VERSION 5.7 ;
  NOWIREEXTENSIONATPIN ON ;
  DIVIDERCHAR "/" ;
  BUSBITCHARS "[]" ;
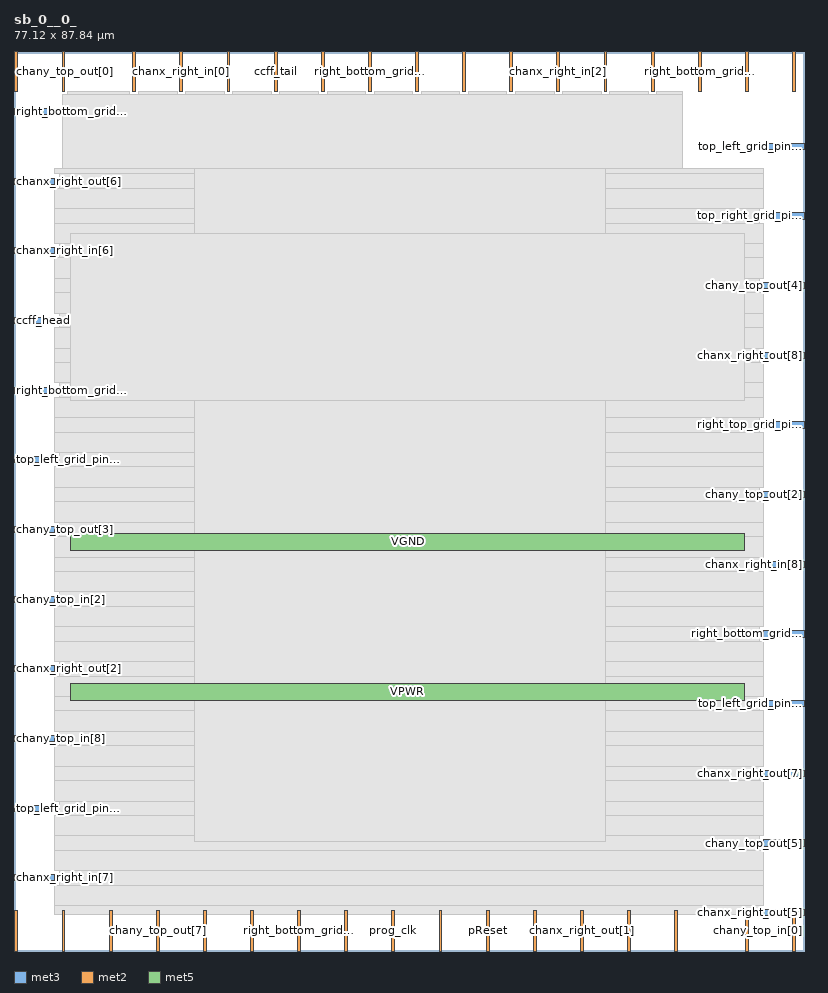
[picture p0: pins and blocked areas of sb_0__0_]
MACRO sb_0__0_
  CLASS BLOCK ;
  FOREIGN sb_0__0_ ;
  ORIGIN 0.000 0.000 ;
  SIZE 77.120 BY 87.840 ;
  PIN ccff_head
    DIRECTION INPUT ;
    PORT
      LAYER met3 ;
        RECT 0.000 61.240 4.000 61.840 ;
    END
  END ccff_head
  PIN ccff_tail
    DIRECTION OUTPUT TRISTATE ;
    PORT
      LAYER met2 ;
        RECT 25.390 83.840 25.670 87.840 ;
    END
  END ccff_tail
  PIN chanx_right_in[0]
    DIRECTION INPUT ;
    PORT
      LAYER met2 ;
        RECT 16.190 83.840 16.470 87.840 ;
    END
  END chanx_right_in[0]
  PIN chanx_right_in[1]
    DIRECTION INPUT ;
    PORT
      LAYER met2 ;
        RECT 0.090 83.840 0.370 87.840 ;
    END
  END chanx_right_in[1]
  PIN chanx_right_in[2]
    DIRECTION INPUT ;
    PORT
      LAYER met2 ;
        RECT 52.990 83.840 53.270 87.840 ;
    END
  END chanx_right_in[2]
  PIN chanx_right_in[3]
    DIRECTION INPUT ;
    PORT
      LAYER met2 ;
        RECT 41.490 0.000 41.770 4.000 ;
    END
  END chanx_right_in[3]
  PIN chanx_right_in[4]
    DIRECTION INPUT ;
    PORT
      LAYER met2 ;
        RECT 50.690 0.000 50.970 4.000 ;
    END
  END chanx_right_in[4]
  PIN chanx_right_in[5]
    DIRECTION INPUT ;
    PORT
      LAYER met2 ;
        RECT 43.790 83.840 44.070 87.840 ;
    END
  END chanx_right_in[5]
  PIN chanx_right_in[6]
    DIRECTION INPUT ;
    PORT
      LAYER met3 ;
        RECT 0.000 68.040 4.000 68.640 ;
    END
  END chanx_right_in[6]
  PIN chanx_right_in[7]
    DIRECTION INPUT ;
    PORT
      LAYER met3 ;
        RECT 0.000 6.840 4.000 7.440 ;
    END
  END chanx_right_in[7]
  PIN chanx_right_in[8]
    DIRECTION INPUT ;
    PORT
      LAYER met3 ;
        RECT 73.120 37.440 77.120 38.040 ;
    END
  END chanx_right_in[8]
  PIN chanx_right_out[0]
    DIRECTION OUTPUT TRISTATE ;
    PORT
      LAYER met2 ;
        RECT 11.590 83.840 11.870 87.840 ;
    END
  END chanx_right_out[0]
  PIN chanx_right_out[1]
    DIRECTION OUTPUT TRISTATE ;
    PORT
      LAYER met2 ;
        RECT 55.290 0.000 55.570 4.000 ;
    END
  END chanx_right_out[1]
  PIN chanx_right_out[2]
    DIRECTION OUTPUT TRISTATE ;
    PORT
      LAYER met3 ;
        RECT 0.000 27.240 4.000 27.840 ;
    END
  END chanx_right_out[2]
  PIN chanx_right_out[3]
    DIRECTION OUTPUT TRISTATE ;
    PORT
      LAYER met2 ;
        RECT 57.590 83.840 57.870 87.840 ;
    END
  END chanx_right_out[3]
  PIN chanx_right_out[4]
    DIRECTION OUTPUT TRISTATE ;
    PORT
      LAYER met2 ;
        RECT 9.290 0.000 9.570 4.000 ;
    END
  END chanx_right_out[4]
  PIN chanx_right_out[5]
    DIRECTION OUTPUT TRISTATE ;
    PORT
      LAYER met3 ;
        RECT 73.120 3.440 77.120 4.040 ;
    END
  END chanx_right_out[5]
  PIN chanx_right_out[6]
    DIRECTION OUTPUT TRISTATE ;
    PORT
      LAYER met3 ;
        RECT 0.000 74.840 4.000 75.440 ;
    END
  END chanx_right_out[6]
  PIN chanx_right_out[7]
    DIRECTION OUTPUT TRISTATE ;
    PORT
      LAYER met3 ;
        RECT 73.120 17.040 77.120 17.640 ;
    END
  END chanx_right_out[7]
  PIN chanx_right_out[8]
    DIRECTION OUTPUT TRISTATE ;
    PORT
      LAYER met3 ;
        RECT 73.120 57.840 77.120 58.440 ;
    END
  END chanx_right_out[8]
  PIN chany_top_in[0]
    DIRECTION INPUT ;
    PORT
      LAYER met2 ;
        RECT 75.990 0.000 76.270 4.000 ;
    END
  END chany_top_in[0]
  PIN chany_top_in[1]
    DIRECTION INPUT ;
    PORT
      LAYER met2 ;
        RECT 29.990 83.840 30.270 87.840 ;
    END
  END chany_top_in[1]
  PIN chany_top_in[2]
    DIRECTION INPUT ;
    PORT
      LAYER met3 ;
        RECT 0.000 34.040 4.000 34.640 ;
    END
  END chany_top_in[2]
  PIN chany_top_in[3]
    DIRECTION INPUT ;
    PORT
      LAYER met2 ;
        RECT 71.390 0.000 71.670 4.000 ;
    END
  END chany_top_in[3]
  PIN chany_top_in[4]
    DIRECTION INPUT ;
    PORT
      LAYER met2 ;
        RECT 48.390 83.840 48.670 87.840 ;
    END
  END chany_top_in[4]
  PIN chany_top_in[5]
    DIRECTION INPUT ;
    PORT
      LAYER met2 ;
        RECT 23.090 0.000 23.370 4.000 ;
    END
  END chany_top_in[5]
  PIN chany_top_in[6]
    DIRECTION INPUT ;
    PORT
      LAYER met2 ;
        RECT 39.190 83.840 39.470 87.840 ;
    END
  END chany_top_in[6]
  PIN chany_top_in[7]
    DIRECTION INPUT ;
    PORT
      LAYER met2 ;
        RECT 64.490 0.000 64.770 4.000 ;
    END
  END chany_top_in[7]
  PIN chany_top_in[8]
    DIRECTION INPUT ;
    PORT
      LAYER met3 ;
        RECT 0.000 20.440 4.000 21.040 ;
    END
  END chany_top_in[8]
  PIN chany_top_out[0]
    DIRECTION OUTPUT TRISTATE ;
    PORT
      LAYER met2 ;
        RECT 4.690 83.840 4.970 87.840 ;
    END
  END chany_top_out[0]
  PIN chany_top_out[1]
    DIRECTION OUTPUT TRISTATE ;
    PORT
      LAYER met2 ;
        RECT 32.290 0.000 32.570 4.000 ;
    END
  END chany_top_out[1]
  PIN chany_top_out[2]
    DIRECTION OUTPUT TRISTATE ;
    PORT
      LAYER met3 ;
        RECT 73.120 44.240 77.120 44.840 ;
    END
  END chany_top_out[2]
  PIN chany_top_out[3]
    DIRECTION OUTPUT TRISTATE ;
    PORT
      LAYER met3 ;
        RECT 0.000 40.840 4.000 41.440 ;
    END
  END chany_top_out[3]
  PIN chany_top_out[4]
    DIRECTION OUTPUT TRISTATE ;
    PORT
      LAYER met3 ;
        RECT 73.120 64.640 77.120 65.240 ;
    END
  END chany_top_out[4]
  PIN chany_top_out[5]
    DIRECTION OUTPUT TRISTATE ;
    PORT
      LAYER met3 ;
        RECT 73.120 10.240 77.120 10.840 ;
    END
  END chany_top_out[5]
  PIN chany_top_out[6]
    DIRECTION OUTPUT TRISTATE ;
    PORT
      LAYER met2 ;
        RECT 18.490 0.000 18.770 4.000 ;
    END
  END chany_top_out[6]
  PIN chany_top_out[7]
    DIRECTION OUTPUT TRISTATE ;
    PORT
      LAYER met2 ;
        RECT 13.890 0.000 14.170 4.000 ;
    END
  END chany_top_out[7]
  PIN chany_top_out[8]
    DIRECTION OUTPUT TRISTATE ;
    PORT
      LAYER met2 ;
        RECT 59.890 0.000 60.170 4.000 ;
    END
  END chany_top_out[8]
  PIN pReset
    DIRECTION INPUT ;
    PORT
      LAYER met2 ;
        RECT 46.090 0.000 46.370 4.000 ;
    END
  END pReset
  PIN prog_clk
    DIRECTION INPUT ;
    PORT
      LAYER met2 ;
        RECT 36.890 0.000 37.170 4.000 ;
    END
  END prog_clk
  PIN right_bottom_grid_pin_11_
    DIRECTION INPUT ;
    PORT
      LAYER met2 ;
        RECT 27.690 0.000 27.970 4.000 ;
    END
  END right_bottom_grid_pin_11_
  PIN right_bottom_grid_pin_13_
    DIRECTION INPUT ;
    PORT
      LAYER met3 ;
        RECT 0.000 81.640 4.000 82.240 ;
    END
  END right_bottom_grid_pin_13_
  PIN right_bottom_grid_pin_15_
    DIRECTION INPUT ;
    PORT
      LAYER met2 ;
        RECT 4.690 0.000 4.970 4.000 ;
    END
  END right_bottom_grid_pin_15_
  PIN right_bottom_grid_pin_1_
    DIRECTION INPUT ;
    PORT
      LAYER met2 ;
        RECT 62.190 83.840 62.470 87.840 ;
    END
  END right_bottom_grid_pin_1_
  PIN right_bottom_grid_pin_3_
    DIRECTION INPUT ;
    PORT
      LAYER met3 ;
        RECT 73.120 30.640 77.120 31.240 ;
    END
  END right_bottom_grid_pin_3_
  PIN right_bottom_grid_pin_5_
    DIRECTION INPUT ;
    PORT
      LAYER met3 ;
        RECT 0.000 54.440 4.000 55.040 ;
    END
  END right_bottom_grid_pin_5_
  PIN right_bottom_grid_pin_7_
    DIRECTION INPUT ;
    PORT
      LAYER met2 ;
        RECT 34.590 83.840 34.870 87.840 ;
    END
  END right_bottom_grid_pin_7_
  PIN right_bottom_grid_pin_9_
    DIRECTION INPUT ;
    PORT
      LAYER met2 ;
        RECT 66.790 83.840 67.070 87.840 ;
    END
  END right_bottom_grid_pin_9_
  PIN right_top_grid_pin_10_
    DIRECTION INPUT ;
    PORT
      LAYER met3 ;
        RECT 73.120 51.040 77.120 51.640 ;
    END
  END right_top_grid_pin_10_
  PIN top_left_grid_pin_11_
    DIRECTION INPUT ;
    PORT
      LAYER met3 ;
        RECT 73.120 23.840 77.120 24.440 ;
    END
  END top_left_grid_pin_11_
  PIN top_left_grid_pin_13_
    DIRECTION INPUT ;
    PORT
      LAYER met3 ;
        RECT 0.000 13.640 4.000 14.240 ;
    END
  END top_left_grid_pin_13_
  PIN top_left_grid_pin_15_
    DIRECTION INPUT ;
    PORT
      LAYER met2 ;
        RECT 71.390 83.840 71.670 87.840 ;
    END
  END top_left_grid_pin_15_
  PIN top_left_grid_pin_1_
    DIRECTION INPUT ;
    PORT
      LAYER met2 ;
        RECT 75.990 83.840 76.270 87.840 ;
    END
  END top_left_grid_pin_1_
  PIN top_left_grid_pin_3_
    DIRECTION INPUT ;
    PORT
      LAYER met3 ;
        RECT 0.000 47.640 4.000 48.240 ;
    END
  END top_left_grid_pin_3_
  PIN top_left_grid_pin_5_
    DIRECTION INPUT ;
    PORT
      LAYER met2 ;
        RECT 20.790 83.840 21.070 87.840 ;
    END
  END top_left_grid_pin_5_
  PIN top_left_grid_pin_7_
    DIRECTION INPUT ;
    PORT
      LAYER met3 ;
        RECT 73.120 78.240 77.120 78.840 ;
    END
  END top_left_grid_pin_7_
  PIN top_left_grid_pin_9_
    DIRECTION INPUT ;
    PORT
      LAYER met2 ;
        RECT 0.090 0.000 0.370 4.000 ;
    END
  END top_left_grid_pin_9_
  PIN top_right_grid_pin_11_
    DIRECTION INPUT ;
    PORT
      LAYER met3 ;
        RECT 73.120 71.440 77.120 72.040 ;
    END
  END top_right_grid_pin_11_
  PIN VPWR
    DIRECTION INPUT ;
    USE POWER ;
    PORT
      LAYER met5 ;
        RECT 5.520 24.480 71.300 26.080 ;
    END
  END VPWR
  PIN VGND
    DIRECTION INPUT ;
    USE GROUND ;
    PORT
      LAYER met5 ;
        RECT 5.520 39.120 71.300 40.720 ;
    END
  END VGND
  OBS
      LAYER li1 ;
        RECT 5.520 10.795 71.300 76.245 ;
      LAYER met1 ;
        RECT 4.670 10.640 71.300 76.400 ;
      LAYER met2 ;
        RECT 5.250 83.560 11.310 83.840 ;
        RECT 12.150 83.560 15.910 83.840 ;
        RECT 16.750 83.560 20.510 83.840 ;
        RECT 21.350 83.560 25.110 83.840 ;
        RECT 25.950 83.560 29.710 83.840 ;
        RECT 30.550 83.560 34.310 83.840 ;
        RECT 35.150 83.560 38.910 83.840 ;
        RECT 39.750 83.560 43.510 83.840 ;
        RECT 44.350 83.560 48.110 83.840 ;
        RECT 48.950 83.560 52.710 83.840 ;
        RECT 53.550 83.560 57.310 83.840 ;
        RECT 58.150 83.560 61.910 83.840 ;
        RECT 62.750 83.560 65.220 83.840 ;
        RECT 4.700 4.280 65.220 83.560 ;
        RECT 5.250 3.555 9.010 4.280 ;
        RECT 9.850 3.555 13.610 4.280 ;
        RECT 14.450 3.555 18.210 4.280 ;
        RECT 19.050 3.555 22.810 4.280 ;
        RECT 23.650 3.555 27.410 4.280 ;
        RECT 28.250 3.555 32.010 4.280 ;
        RECT 32.850 3.555 36.610 4.280 ;
        RECT 37.450 3.555 41.210 4.280 ;
        RECT 42.050 3.555 45.810 4.280 ;
        RECT 46.650 3.555 50.410 4.280 ;
        RECT 51.250 3.555 55.010 4.280 ;
        RECT 55.850 3.555 59.610 4.280 ;
        RECT 60.450 3.555 64.210 4.280 ;
        RECT 65.050 3.555 65.220 4.280 ;
      LAYER met3 ;
        RECT 4.000 75.840 73.120 76.325 ;
        RECT 4.400 74.440 73.120 75.840 ;
        RECT 4.000 72.440 73.120 74.440 ;
        RECT 4.000 71.040 72.720 72.440 ;
        RECT 4.000 69.040 73.120 71.040 ;
        RECT 4.400 67.640 73.120 69.040 ;
        RECT 4.000 65.640 73.120 67.640 ;
        RECT 4.000 64.240 72.720 65.640 ;
        RECT 4.000 62.240 73.120 64.240 ;
        RECT 4.400 60.840 73.120 62.240 ;
        RECT 4.000 58.840 73.120 60.840 ;
        RECT 4.000 57.440 72.720 58.840 ;
        RECT 4.000 55.440 73.120 57.440 ;
        RECT 4.400 54.040 73.120 55.440 ;
        RECT 4.000 52.040 73.120 54.040 ;
        RECT 4.000 50.640 72.720 52.040 ;
        RECT 4.000 48.640 73.120 50.640 ;
        RECT 4.400 47.240 73.120 48.640 ;
        RECT 4.000 45.240 73.120 47.240 ;
        RECT 4.000 43.840 72.720 45.240 ;
        RECT 4.000 41.840 73.120 43.840 ;
        RECT 4.400 40.440 73.120 41.840 ;
        RECT 4.000 38.440 73.120 40.440 ;
        RECT 4.000 37.040 72.720 38.440 ;
        RECT 4.000 35.040 73.120 37.040 ;
        RECT 4.400 33.640 73.120 35.040 ;
        RECT 4.000 31.640 73.120 33.640 ;
        RECT 4.000 30.240 72.720 31.640 ;
        RECT 4.000 28.240 73.120 30.240 ;
        RECT 4.400 26.840 73.120 28.240 ;
        RECT 4.000 24.840 73.120 26.840 ;
        RECT 4.000 23.440 72.720 24.840 ;
        RECT 4.000 21.440 73.120 23.440 ;
        RECT 4.400 20.040 73.120 21.440 ;
        RECT 4.000 18.040 73.120 20.040 ;
        RECT 4.000 16.640 72.720 18.040 ;
        RECT 4.000 14.640 73.120 16.640 ;
        RECT 4.400 13.240 73.120 14.640 ;
        RECT 4.000 11.240 73.120 13.240 ;
        RECT 4.000 9.840 72.720 11.240 ;
        RECT 4.000 7.840 73.120 9.840 ;
        RECT 4.400 6.440 73.120 7.840 ;
        RECT 4.000 4.440 73.120 6.440 ;
        RECT 4.000 3.575 72.720 4.440 ;
      LAYER met4 ;
        RECT 17.570 10.640 57.730 76.400 ;
      LAYER met5 ;
        RECT 5.520 53.760 71.300 70.000 ;
  END
END sb_0__0_
END LIBRARY

